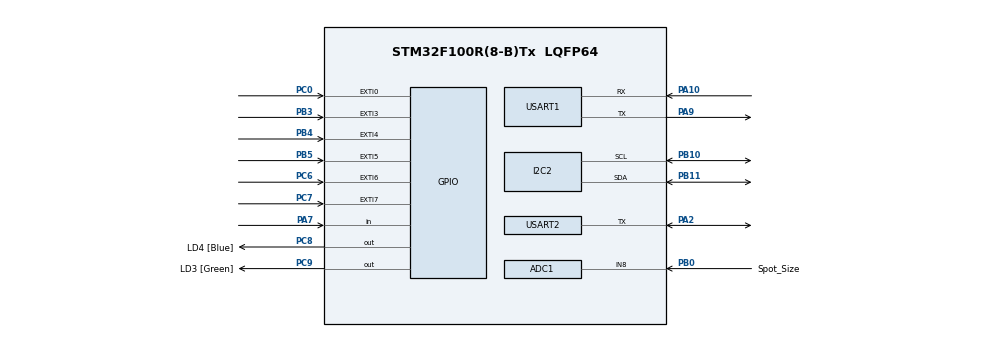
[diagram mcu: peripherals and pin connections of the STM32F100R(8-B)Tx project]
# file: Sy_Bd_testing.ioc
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ADC1.Channel-0\#ChannelRegularConversion=ADC_CHANNEL_8
ADC1.NbrOfConversionFlag=1
ADC1.Rank-0\#ChannelRegularConversion=1
ADC1.SamplingTime-0\#ChannelRegularConversion=ADC_SAMPLETIME_1CYCLE_5
ADC1.master=1
Dma.Request0=USART2_RX
Dma.Request1=USART2_TX
Dma.USART2_RX.0.Direction=DMA_PERIPH_TO_MEMORY
Dma.USART2_RX.0.Instance=DMA1_Channel6
Dma.USART2_RX.0.MemDataAlignment=DMA_MDATAALIGN_BYTE
Dma.USART2_RX.0.MemInc=DMA_MINC_ENABLE
Dma.USART2_RX.0.Mode=DMA_NORMAL
Dma.USART2_RX.0.PeriphDataAlignment=DMA_PDATAALIGN_BYTE
Dma.USART2_RX.0.PeriphInc=DMA_PINC_DISABLE
Dma.USART2_RX.0.Priority=DMA_PRIORITY_LOW
Dma.USART2_TX.1.Direction=DMA_MEMORY_TO_PERIPH
Dma.USART2_TX.1.Instance=DMA1_Channel7
Dma.USART2_TX.1.MemDataAlignment=DMA_MDATAALIGN_BYTE
Dma.USART2_TX.1.MemInc=DMA_MINC_ENABLE
Dma.USART2_TX.1.Mode=DMA_NORMAL
Dma.USART2_TX.1.PeriphDataAlignment=DMA_PDATAALIGN_BYTE
Dma.USART2_TX.1.PeriphInc=DMA_PINC_DISABLE
Dma.USART2_TX.1.Priority=DMA_PRIORITY_LOW
Mcu.Family=STM32F1
Mcu.Name=STM32F100R(8-B)Tx
Mcu.Package=LQFP64
NVIC.DMA1_Channel6_IRQn=true\:0\:0\:false\:false\:true\:false\:true
NVIC.DMA1_Channel7_IRQn=true\:0\:0\:false\:false\:true\:false\:true
NVIC.EXTI0_IRQn=true\:0\:0\:false\:false\:true\:true\:true
NVIC.EXTI3_IRQn=true\:0\:0\:false\:false\:true\:true\:true
NVIC.EXTI4_IRQn=true\:0\:0\:false\:false\:true\:true\:true
NVIC.EXTI9_5_IRQn=true\:0\:0\:false\:false\:true\:true\:true
NVIC.PriorityGroup=NVIC_PRIORITYGROUP_4
NVIC.USART1_IRQn=true\:0\:0\:false\:false\:true\:true\:true
PA0-WKUP.Mode=SYS_WakeUp0
PA0-WKUP.Signal=SYS_WKUP
PA10.Mode=Asynchronous
PA10.Signal=USART1_RX
PA13.GPIO_Label=TMS_SWDIO
PA13.Mode=Serial_Wire
PA13.Signal=SYS_JTMS-SWDIO
PA14.GPIO_Label=TCK_SWCLK
PA14.Mode=Serial_Wire
PA14.Signal=SYS_JTCK-SWCLK
PA2.Mode=Half_duplex(single_wire_mode)
PA2.Signal=USART2_TX
PA7.Signal=GPIO_Input
PA9.Mode=Asynchronous
PA9.Signal=USART1_TX
PB0.GPIO_Label=Spot_Size
PB0.Signal=ADCx_IN8
PB10.Mode=I2C
PB10.Signal=I2C2_SCL
PB11.Mode=I2C
PB11.Signal=I2C2_SDA
PB3.Signal=GPXTI3
PB4.Signal=GPXTI4
PB5.Signal=GPXTI5
PC0.Signal=GPXTI0
PC14-OSC32_IN.Mode=LSE-External-Oscillator
PC14-OSC32_IN.Signal=RCC_OSC32_IN
PC15-OSC32_OUT.Mode=LSE-External-Oscillator
PC15-OSC32_OUT.Signal=RCC_OSC32_OUT
PC6.Signal=GPXTI6
PC7.Signal=GPXTI7
PC8.GPIO_Label=LD4 [Blue]
PC8.Signal=GPIO_Output
PC9.GPIO_Label=LD3 [Green]
PC9.Signal=GPIO_Output
PD0-OSC_IN.Mode=HSE-External-Oscillator
PD0-OSC_IN.Signal=RCC_OSC_IN
PD1-OSC_OUT.Mode=HSE-External-Oscillator
PD1-OSC_OUT.Signal=RCC_OSC_OUT
ProjectManager.HeapSize=0x200
ProjectManager.StackSize=0x400
ProjectManager.TargetToolchain=STM32CubeIDE
RCC.APB1Freq_Value=8000000
RCC.APB2Freq_Value=8000000
SH.ADCx_IN8.0=ADC1_IN8,IN8
USART1.VirtualMode=VM_ASYNC
USART2.VirtualMode=VM_ASYNC
board=STM32VLDISCOVERY

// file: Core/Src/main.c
/* USER CODE BEGIN Header */
/** Machine Serial.No: 23KCON-1_Sy
  ******************************************************************************
  * @file           : main.c
  * @brief          : Main program body
  ******************************************************************************
  * @attention
  *
  * Copyright (c) 2024 STMicroelectronics.
  * All rights reserved.
  *
  * This software is licensed under terms that can be found in the LICENSE file
  * in the root directory of this software component.
  * If no LICENSE file comes with this software, it is provided AS-IS.
  *
  ******************************************************************************
  */
/* USER CODE END Header */
#include "main.h"
#include "stm32f1xx_hal.h"
#include <stdio.h>
#include<string.h>

uint8_t RxBuffer[9]={0};//Rxbuffer
uint8_t Receive = 0;

uint8_t pattern;
float spot_size = 0.2,Temp_spot_size = 0.2;
uint16_t AD_RES=0;

#define SHT4x_ADDR         (0x44 << 1)  // Shifted for HAL
#define SHT4x_MEASURE_CMD  0xFD         // High precision measurement
#define SHT4x_SERIAL_CMD   0x89         // Read serial number

void SHT4x_readSerialNumber();
void SHT40_readMeasurement();

char msg[500];
int Presence,Initial_Temp=0;
volatile uint8_t isTxed = 0,isRxed=0;
uint8_t RxData[8],Temp_LSB,Temp_MSB;
float Temperature;
float Console_Temperature = 26.0;
float Board_Temperature;
void uart_init(uint32_t);
int DS18B20_Start(void);
void DS18B20_Write (uint8_t);
uint8_t DS18B20_Read (void);

ADC_HandleTypeDef hadc1;

I2C_HandleTypeDef hi2c2;

UART_HandleTypeDef huart1;
UART_HandleTypeDef huart2;
DMA_HandleTypeDef hdma_usart2_rx;
DMA_HandleTypeDef hdma_usart2_tx;

void SystemClock_Config(void);
static void MX_GPIO_Init(void);
static void MX_ADC1_Init(void);
static void MX_DMA_Init(void);
static void MX_USART2_UART_Init(void);
static void MX_USART1_UART_Init(void);
static void MX_I2C2_Init(void);

void Spot_size_read();

int main(void)
{

  /* MCU Configuration--------------------------------------------------------*/

  /* Reset of all peripherals, Initializes the Flash interface and the Systick. */
  HAL_Init();

  /* Configure the system clock */
  SystemClock_Config();

  /* Initialize all configured peripherals */
  MX_GPIO_Init();
  MX_ADC1_Init();
  MX_DMA_Init();
  MX_USART2_UART_Init();
  MX_USART1_UART_Init();
  MX_I2C2_Init();
  /* USER CODE BEGIN 2 */
  HAL_ADC_Start(&hadc1);
  /* USER CODE END 2 */
/*  HAL_GPIO_WritePin(GPIOB, GPIO_PIN_2, 1);
  HAL_GPIO_WritePin(GPIOB, GPIO_PIN_3, 1);*/
  /* Infinite loop */
  while (1)
  {
	   	  while( HAL_GPIO_ReadPin(GPIOA, GPIO_PIN_7) == 0){};//Commented for Testing
		  //Spot_size_read();

		  Receive=0;

		  HAL_UART_Receive_IT(&huart1,&Receive,sizeof(Receive));

		  HAL_GPIO_WritePin(GPIOC, GPIO_PIN_8, 0);

	      /* USER CODE BEGIN 3 */
    /* USER CODE BEGIN 3 */
  }
  /* USER CODE END 3 */
}

void HAL_UART_RxCpltCallback(UART_HandleTypeDef *huart)
{
	//HAL_GPIO_WritePin(GPIOC, GPIO_PIN_8, 1);
	if (huart->Instance == USART2)
	{
	isRxed = 1;
	}
	else if(huart->Instance == USART1)
	{

	HAL_UART_Receive_IT(&huart1, &Receive,sizeof(Receive));
	//HAL_GPIO_WritePin(GPIOC, GPIO_PIN_8, 1);
		pattern = Receive;
		if( Receive == 0x5A)
		{
			 HAL_GPIO_WritePin(GPIOC, GPIO_PIN_8, 1);

		}
	}
}

void Spot_size_read()
{
  /**********************************************************************
               ADC for Spot size 100um, 200um, 300um, 400um, 500um
   **********************************************************************/

  if(HAL_ADC_PollForConversion(&hadc1, 1000) == HAL_OK) // Poll ADC1 Perihperal & TimeOut = 1mSec
 {
       AD_RES = HAL_ADC_GetValue(&hadc1); // Read The ADC Conversion Result & Map It To PWM DutyCycle

 }

  if ((AD_RES >= 2200) && (AD_RES < 4000))
  {
	  spot_size=0.1;
  }
  else if ((AD_RES > 1800) && (AD_RES <= 2200))
  {
	  spot_size = 0.2;
  }
  else if ((AD_RES > 1410) && (AD_RES <= 1850))
  {
	  spot_size = 0.3;
  }
  else if ((AD_RES > 1110) && (AD_RES <= 1400))
  {
	  spot_size = 0.4;
  }
  else if ((AD_RES <= 1100))//((AD_RES > 100) && (AD_RES <= 800))
  {
	  spot_size = 0.5;
  }

  if(Temp_spot_size == spot_size)
  {
	//HAL_GPIO_WritePin(GPIOC, GPIO_PIN_8, 0);
  }
  else
  {
	  Temp_spot_size = spot_size;
	  //HAL_GPIO_WritePin(GPIOC, GPIO_PIN_8, 1);
  }

 }

void HAL_GPIO_EXTI_Callback(uint16_t GPIO_Pin)
{
    if((GPIO_Pin == GPIO_PIN_7)||(GPIO_Pin == GPIO_PIN_6)||(GPIO_Pin == GPIO_PIN_0)||(GPIO_Pin == GPIO_PIN_1)||(GPIO_Pin == GPIO_PIN_4)||(GPIO_Pin == GPIO_PIN_5)||(GPIO_Pin == GPIO_PIN_3))//) // If The INT Source Is EXTI Line6 (C6 Pin)
    {
    	HAL_GPIO_WritePin(GPIOC, GPIO_PIN_8, 1); // Toggle The Output (LED) Pin
    }

}

void SystemClock_Config(void)
{
  RCC_OscInitTypeDef RCC_OscInitStruct = {0};
  RCC_ClkInitTypeDef RCC_ClkInitStruct = {0};
  RCC_PeriphCLKInitTypeDef PeriphClkInit = {0};

  /** Initializes the RCC Oscillators according to the specified parameters
  * in the RCC_OscInitTypeDef structure.
  */
  RCC_OscInitStruct.OscillatorType = RCC_OSCILLATORTYPE_HSI;
  RCC_OscInitStruct.HSIState = RCC_HSI_ON;
  RCC_OscInitStruct.HSICalibrationValue = RCC_HSICALIBRATION_DEFAULT;
  RCC_OscInitStruct.PLL.PLLState = RCC_PLL_NONE;
  if (HAL_RCC_OscConfig(&RCC_OscInitStruct) != HAL_OK)
  {
    Error_Handler();
  }
  /** Initializes the CPU, AHB and APB buses clocks
  */
  RCC_ClkInitStruct.ClockType = RCC_CLOCKTYPE_HCLK|RCC_CLOCKTYPE_SYSCLK
                              |RCC_CLOCKTYPE_PCLK1|RCC_CLOCKTYPE_PCLK2;
  RCC_ClkInitStruct.SYSCLKSource = RCC_SYSCLKSOURCE_HSI;
  RCC_ClkInitStruct.AHBCLKDivider = RCC_SYSCLK_DIV1;
  RCC_ClkInitStruct.APB1CLKDivider = RCC_HCLK_DIV1;
  RCC_ClkInitStruct.APB2CLKDivider = RCC_HCLK_DIV1;

  if (HAL_RCC_ClockConfig(&RCC_ClkInitStruct, FLASH_LATENCY_0) != HAL_OK)
  {
    Error_Handler();
  }
  PeriphClkInit.PeriphClockSelection = RCC_PERIPHCLK_ADC;
  PeriphClkInit.AdcClockSelection = RCC_ADCPCLK2_DIV2;
  if (HAL_RCCEx_PeriphCLKConfig(&PeriphClkInit) != HAL_OK)
  {
    Error_Handler();
  }
}

static void MX_ADC1_Init(void)
{

  ADC_ChannelConfTypeDef sConfig = {0};

  /* USER CODE BEGIN ADC1_Init 1 */
  __HAL_RCC_ADC1_CLK_ENABLE();

     __HAL_RCC_GPIOB_CLK_ENABLE();

  /* USER CODE END ADC1_Init 1 */
  /** Common config
  */
  hadc1.Instance = ADC1;
  hadc1.Init.ScanConvMode = ADC_SCAN_DISABLE;
  hadc1.Init.ContinuousConvMode = DISABLE;
  hadc1.Init.DiscontinuousConvMode = DISABLE;
  hadc1.Init.ExternalTrigConv = ADC_SOFTWARE_START;
  hadc1.Init.DataAlign = ADC_DATAALIGN_RIGHT;
  hadc1.Init.NbrOfConversion = 1;
  if (HAL_ADC_Init(&hadc1) != HAL_OK)
  {
    Error_Handler();
  }
  /** Configure Regular Channel
  */
  sConfig.Channel = ADC_CHANNEL_8;
  sConfig.Rank = ADC_REGULAR_RANK_1;
  sConfig.SamplingTime = ADC_SAMPLETIME_1CYCLE_5;
  if (HAL_ADC_ConfigChannel(&hadc1, &sConfig) != HAL_OK)
  {
    Error_Handler();
  }

}

static void MX_I2C2_Init(void)
{

  hi2c2.Instance = I2C2;
  hi2c2.Init.ClockSpeed = 100000;
  hi2c2.Init.DutyCycle = I2C_DUTYCYCLE_2;
  hi2c2.Init.OwnAddress1 = 0;
  hi2c2.Init.AddressingMode = I2C_ADDRESSINGMODE_7BIT;
  hi2c2.Init.DualAddressMode = I2C_DUALADDRESS_DISABLE;
  hi2c2.Init.OwnAddress2 = 0;
  hi2c2.Init.GeneralCallMode = I2C_GENERALCALL_DISABLE;
  hi2c2.Init.NoStretchMode = I2C_NOSTRETCH_DISABLE;
  if (HAL_I2C_Init(&hi2c2) != HAL_OK)
  {
    Error_Handler();
  }

}

static void MX_USART1_UART_Init(void)
{

  huart1.Instance = USART1;
  huart1.Init.BaudRate = 115200;
  huart1.Init.WordLength = UART_WORDLENGTH_8B;
  huart1.Init.StopBits = UART_STOPBITS_1;
  huart1.Init.Parity = UART_PARITY_NONE;
  huart1.Init.Mode = UART_MODE_TX_RX;
  huart1.Init.HwFlowCtl = UART_HWCONTROL_NONE;
  huart1.Init.OverSampling = UART_OVERSAMPLING_16;
  if (HAL_UART_Init(&huart1) != HAL_OK)
  {
    Error_Handler();
  }

}

static void MX_USART2_UART_Init(void)
{

  huart2.Instance = USART2;
  huart2.Init.BaudRate = 115200;
  huart2.Init.WordLength = UART_WORDLENGTH_8B;
  huart2.Init.StopBits = UART_STOPBITS_1;
  huart2.Init.Parity = UART_PARITY_NONE;
  huart2.Init.Mode = UART_MODE_TX_RX;
  huart2.Init.HwFlowCtl = UART_HWCONTROL_NONE;
  huart2.Init.OverSampling = UART_OVERSAMPLING_16;
  if (HAL_HalfDuplex_Init(&huart2) != HAL_OK)
  {
    Error_Handler();
  }

}

static void MX_DMA_Init(void)
{

  /* DMA controller clock enable */
  __HAL_RCC_DMA1_CLK_ENABLE();

  /* DMA interrupt init */
  /* DMA1_Channel6_IRQn interrupt configuration */
  HAL_NVIC_SetPriority(DMA1_Channel6_IRQn, 0, 0);
  HAL_NVIC_EnableIRQ(DMA1_Channel6_IRQn);
  /* DMA1_Channel7_IRQn interrupt configuration */
  HAL_NVIC_SetPriority(DMA1_Channel7_IRQn, 0, 0);
  HAL_NVIC_EnableIRQ(DMA1_Channel7_IRQn);

}

static void MX_GPIO_Init(void)
{
  GPIO_InitTypeDef GPIO_InitStruct = {0};

  /* GPIO Ports Clock Enable */
  __HAL_RCC_GPIOC_CLK_ENABLE();
  __HAL_RCC_GPIOD_CLK_ENABLE();
  __HAL_RCC_GPIOA_CLK_ENABLE();
  __HAL_RCC_GPIOB_CLK_ENABLE();

  /*Configure GPIO pin Output Level */
  HAL_GPIO_WritePin(GPIOC, LD4_Pin|LD3_Pin, GPIO_PIN_RESET);

  /*Configure GPIO pins : PC0 PC6 PC7 */
  GPIO_InitStruct.Pin = GPIO_PIN_0|GPIO_PIN_6;
  GPIO_InitStruct.Mode = GPIO_MODE_IT_RISING;
  GPIO_InitStruct.Pull = GPIO_NOPULL;
  HAL_GPIO_Init(GPIOC, &GPIO_InitStruct);

  GPIO_InitStruct.Pin = GPIO_PIN_7;
  GPIO_InitStruct.Mode = GPIO_MODE_IT_FALLING;
  GPIO_InitStruct.Pull = GPIO_PULLUP;
  HAL_GPIO_Init(GPIOC, &GPIO_InitStruct);

  /*Configure GPIO pin : PA7 */
  GPIO_InitStruct.Pin = GPIO_PIN_7;
  GPIO_InitStruct.Mode = GPIO_MODE_INPUT;
  GPIO_InitStruct.Pull = GPIO_NOPULL;
  HAL_GPIO_Init(GPIOA, &GPIO_InitStruct);

  /*Configure GPIO pins : LD4_Pin LD3_Pin */
  GPIO_InitStruct.Pin = LD4_Pin|LD3_Pin;
  GPIO_InitStruct.Mode = GPIO_MODE_OUTPUT_PP;
  GPIO_InitStruct.Pull = GPIO_NOPULL;
  GPIO_InitStruct.Speed = GPIO_SPEED_FREQ_LOW;
  HAL_GPIO_Init(GPIOC, &GPIO_InitStruct);

  GPIO_InitStruct.Pin = GPIO_PIN_10|GPIO_PIN_11;
  GPIO_InitStruct.Mode = GPIO_MODE_OUTPUT_PP;
  GPIO_InitStruct.Pull = GPIO_PULLUP;
  GPIO_InitStruct.Speed = GPIO_SPEED_FREQ_LOW;
  HAL_GPIO_Init(GPIOC, &GPIO_InitStruct);

/*  GPIO_InitStruct.Pin = GPIO_PIN_2;
  GPIO_InitStruct.Mode = GPIO_MODE_OUTPUT_PP;
  GPIO_InitStruct.Pull = GPIO_NOPULL;
  GPIO_InitStruct.Speed = GPIO_SPEED_FREQ_LOW;
  HAL_GPIO_Init(GPIOB, &GPIO_InitStruct);

  GPIO_InitStruct.Pin = GPIO_PIN_3;
  GPIO_InitStruct.Mode = GPIO_MODE_OUTPUT_PP;
  GPIO_InitStruct.Pull = GPIO_NOPULL;
  GPIO_InitStruct.Speed = GPIO_SPEED_FREQ_LOW;
  HAL_GPIO_Init(GPIOB, &GPIO_InitStruct);*/

  /*Configure GPIO pins : PB1 PB4 PB5 */
  GPIO_InitStruct.Pin = GPIO_PIN_1;//ENDO
  GPIO_InitStruct.Mode = GPIO_MODE_IT_FALLING;
  GPIO_InitStruct.Pull = GPIO_NOPULL;
  HAL_GPIO_Init(GPIOB, &GPIO_InitStruct);

  GPIO_InitStruct.Pin = GPIO_PIN_4;//LIO
  GPIO_InitStruct.Mode = GPIO_MODE_IT_FALLING;
  GPIO_InitStruct.Pull = GPIO_NOPULL;
  HAL_GPIO_Init(GPIOB, &GPIO_InitStruct);

  GPIO_InitStruct.Pin = GPIO_PIN_5;//SLA
  GPIO_InitStruct.Mode = GPIO_MODE_IT_FALLING;
  GPIO_InitStruct.Pull = GPIO_NOPULL;
  HAL_GPIO_Init(GPIOB, &GPIO_InitStruct);

  GPIO_InitStruct.Pin = GPIO_PIN_3;//For Fibre Detection
  GPIO_InitStruct.Mode = GPIO_MODE_IT_RISING;
  GPIO_InitStruct.Pull = GPIO_NOPULL;
  HAL_GPIO_Init(GPIOC, &GPIO_InitStruct);

  /* EXTI interrupt init*/
  HAL_NVIC_SetPriority(EXTI0_IRQn, 0, 0);
  HAL_NVIC_EnableIRQ(EXTI0_IRQn);

  HAL_NVIC_SetPriority(EXTI1_IRQn, 1, 0);
  HAL_NVIC_EnableIRQ(EXTI1_IRQn);

  HAL_NVIC_SetPriority(EXTI3_IRQn, 1, 0);
  HAL_NVIC_EnableIRQ(EXTI3_IRQn);

  HAL_NVIC_SetPriority(EXTI4_IRQn, 1, 1);
  HAL_NVIC_EnableIRQ(EXTI4_IRQn);

  HAL_NVIC_SetPriority(EXTI9_5_IRQn, 0, 0);
  HAL_NVIC_EnableIRQ(EXTI9_5_IRQn);

}

void Error_Handler(void)
{
  __disable_irq();
  while (1)
  {
  }
}
